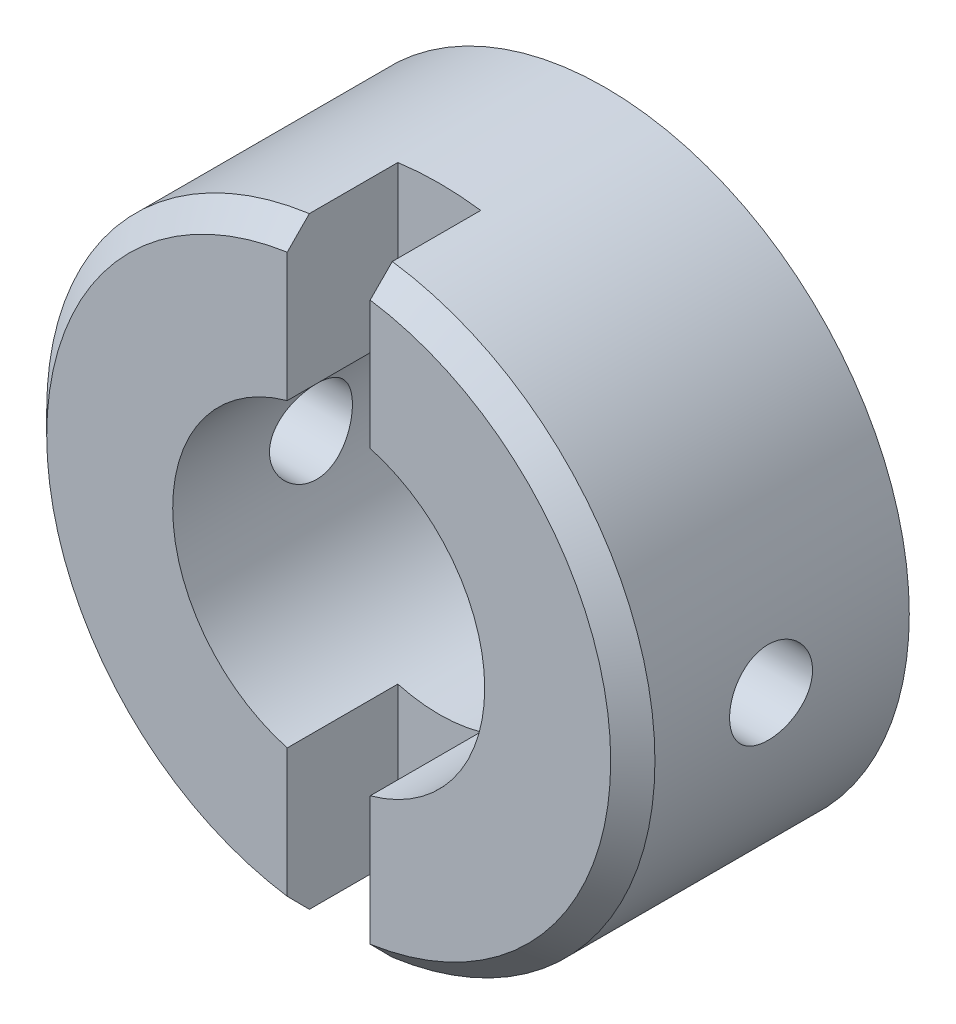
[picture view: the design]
ISO-10303-21;
HEADER;
FILE_DESCRIPTION(('STEP AP214'),'2;1');
FILE_NAME('part.step','',(''),(''),'','','');
FILE_SCHEMA(('AUTOMOTIVE_DESIGN { 1 0 10303 214 1 1 1 1 }'));
ENDSEC;
DATA;
#1=APPLICATION_CONTEXT('core data for automotive mechanical design processes');
#2=APPLICATION_PROTOCOL_DEFINITION('international standard','automotive_design',2000,#1);
#3=PRODUCT_CONTEXT('',#1,'mechanical');
#4=PRODUCT('Part','Part','',(#3));
#5=PRODUCT_RELATED_PRODUCT_CATEGORY('part','',(#4));
#6=PRODUCT_DEFINITION_FORMATION('','',#4);
#7=PRODUCT_DEFINITION_CONTEXT('part definition',#1,'design');
#8=PRODUCT_DEFINITION('design','',#6,#7);
#9=PRODUCT_DEFINITION_SHAPE('','',#8);
#10=(LENGTH_UNIT() NAMED_UNIT(*) SI_UNIT(.MILLI.,.METRE.));
#11=(NAMED_UNIT(*) PLANE_ANGLE_UNIT() SI_UNIT($,.RADIAN.));
#12=(NAMED_UNIT(*) SI_UNIT($,.STERADIAN.) SOLID_ANGLE_UNIT());
#13=UNCERTAINTY_MEASURE_WITH_UNIT(LENGTH_MEASURE(1.E-05),#10,'distance_accuracy_value','');
#14=(GEOMETRIC_REPRESENTATION_CONTEXT(3) GLOBAL_UNCERTAINTY_ASSIGNED_CONTEXT((#13)) GLOBAL_UNIT_ASSIGNED_CONTEXT((#10,
#11,#12)) REPRESENTATION_CONTEXT('',''));
#15=CARTESIAN_POINT('',(0.,0.,0.));
#16=DIRECTION('',(0.,0.,1.));
#17=DIRECTION('',(1.,0.,0.));
#18=AXIS2_PLACEMENT_3D('',#15,#16,#17);
#19=CARTESIAN_POINT('',(0.,0.,0.));
#20=DIRECTION('',(0.,0.,1.));
#21=DIRECTION('',(1.,0.,0.));
#22=AXIS2_PLACEMENT_3D('',#19,#20,#21);
#23=PLANE('',#22);
#24=DIRECTION('',(0.,1.,0.));
#25=VECTOR('',#24,1.);
#26=CARTESIAN_POINT('',(1.5,10.8972473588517,-1.70530256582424E-10));
#27=LINE('',#26,#25);
#28=CARTESIAN_POINT('',(1.5,-10.0891030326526,-1.70530256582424E-10));
#29=VERTEX_POINT('',#28);
#30=CARTESIAN_POINT('',(1.5,-5.43983887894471,-1.70530256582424E-10));
#31=VERTEX_POINT('',#30);
#32=EDGE_CURVE('E175',#29,#31,#27,.T.);
#33=ORIENTED_EDGE('',*,*,#32,.F.);
#34=CARTESIAN_POINT('',(0.,0.,0.));
#35=DIRECTION('',(0.,0.,1.));
#36=DIRECTION('',(1.,0.,0.));
#37=AXIS2_PLACEMENT_3D('',#34,#35,#36);
#38=CIRCLE('',#37,10.2);
#39=CARTESIAN_POINT('',(1.5,10.0891030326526,-1.70530256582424E-10));
#40=VERTEX_POINT('',#39);
#41=EDGE_CURVE('E191',#29,#40,#38,.T.);
#42=ORIENTED_EDGE('',*,*,#41,.T.);
#43=CARTESIAN_POINT('',(1.5,5.43983887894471,-1.70530256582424E-10));
#44=VERTEX_POINT('',#43);
#45=EDGE_CURVE('E171',#44,#40,#27,.T.);
#46=ORIENTED_EDGE('',*,*,#45,.F.);
#47=CARTESIAN_POINT('',(0.,0.,0.));
#48=DIRECTION('',(0.,0.,1.));
#49=DIRECTION('',(1.,0.,0.));
#50=AXIS2_PLACEMENT_3D('',#47,#48,#49);
#51=CIRCLE('',#50,5.642858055);
#52=EDGE_CURVE('E187',#31,#44,#51,.T.);
#53=ORIENTED_EDGE('',*,*,#52,.F.);
#54=EDGE_LOOP('',(#33,#42,#46,#53));
#55=FACE_BOUND('',#54,.T.);
#56=ADVANCED_FACE('F50',(#55),#23,.T.);
#57=CARTESIAN_POINT('',(0.,0.,0.));
#58=DIRECTION('',(0.,0.,-1.));
#59=DIRECTION('',(-1.,0.,0.));
#60=AXIS2_PLACEMENT_3D('',#57,#58,#59);
#61=CONICAL_SURFACE('',#60,10.2,0.785398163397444);
#62=CARTESIAN_POINT('',(1.5,-23.9829507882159,-13.8298133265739));
#63=CARTESIAN_POINT('',(1.5,-23.1697960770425,-13.0182561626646));
#64=CARTESIAN_POINT('',(1.5,-22.3565720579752,-12.2067684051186));
#65=CARTESIAN_POINT('',(1.5,-20.7298859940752,-10.5840045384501));
#66=CARTESIAN_POINT('',(1.5,-19.9164239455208,-9.77272843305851));
#67=CARTESIAN_POINT('',(1.5,-18.2888908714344,-8.15019003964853));
#68=CARTESIAN_POINT('',(1.5,-17.4748197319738,-7.33892786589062));
#69=CARTESIAN_POINT('',(1.5,-15.8462200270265,-5.71688912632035));
#70=CARTESIAN_POINT('',(1.5,-15.0316914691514,-4.90611255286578));
#71=CARTESIAN_POINT('',(1.5,-13.3679166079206,-3.25150833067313));
#72=CARTESIAN_POINT('',(1.5,-12.5186388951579,-2.40771224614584));
#73=CARTESIAN_POINT('',(1.5,-11.2436084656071,-1.14309787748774));
#74=CARTESIAN_POINT('',(1.5,-10.8184018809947,-0.721729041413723));
#75=CARTESIAN_POINT('',(1.5,-9.96746963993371,0.120480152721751));
#76=CARTESIAN_POINT('',(1.5,-9.54174398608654,0.54132051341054));
#77=CARTESIAN_POINT('',(1.5,-8.68962827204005,1.38212855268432));
#78=CARTESIAN_POINT('',(1.5,-8.26323839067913,1.8020964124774));
#79=CARTESIAN_POINT('',(1.5,-7.40927555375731,2.64084579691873));
#80=CARTESIAN_POINT('',(1.5,-6.98170257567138,3.05962729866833));
#81=CARTESIAN_POINT('',(1.5,-6.3388656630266,3.68624687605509));
#82=CARTESIAN_POINT('',(1.5,-6.12434986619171,3.89485219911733));
#83=CARTESIAN_POINT('',(1.5,-5.69463736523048,4.31136007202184));
#84=CARTESIAN_POINT('',(1.5,-5.47944066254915,4.51926262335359));
#85=CARTESIAN_POINT('',(1.5,-5.0481094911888,4.93407979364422));
#86=CARTESIAN_POINT('',(1.5,-4.83197505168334,5.1409944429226));
#87=CARTESIAN_POINT('',(1.5,-4.39834846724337,5.55339520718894));
#88=CARTESIAN_POINT('',(1.5,-4.1808563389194,5.75888133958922));
#89=CARTESIAN_POINT('',(1.5,-3.90376234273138,6.01802196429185));
#90=CARTESIAN_POINT('',(1.5,-3.84512620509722,6.07270919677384));
#91=CARTESIAN_POINT('',(1.5,-3.72768146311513,6.18189848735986));
#92=CARTESIAN_POINT('',(1.5,-3.66887285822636,6.23640054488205));
#93=CARTESIAN_POINT('',(1.5,-3.49215401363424,6.3995935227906));
#94=CARTESIAN_POINT('',(1.5,-3.37395242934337,6.50796966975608));
#95=CARTESIAN_POINT('',(1.5,-3.13700278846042,6.72317143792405));
#96=CARTESIAN_POINT('',(1.5,-3.01825878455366,6.83000151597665));
#97=CARTESIAN_POINT('',(1.5,-2.77941542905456,7.0421331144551));
#98=CARTESIAN_POINT('',(1.5,-2.65931612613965,7.14743468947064));
#99=CARTESIAN_POINT('',(1.5,-2.45761599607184,7.32107625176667));
#100=CARTESIAN_POINT('',(1.5,-2.37654045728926,7.39002559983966));
#101=CARTESIAN_POINT('',(1.5,-2.21332363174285,7.52664946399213));
#102=CARTESIAN_POINT('',(1.5,-2.13118237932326,7.59432402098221));
#103=CARTESIAN_POINT('',(1.5,-1.96490717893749,7.72847699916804));
#104=CARTESIAN_POINT('',(1.5,-1.88076292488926,7.79494269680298));
#105=CARTESIAN_POINT('',(1.5,-1.71065638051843,7.92549614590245));
#106=CARTESIAN_POINT('',(1.5,-1.62469433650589,7.98958421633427));
#107=CARTESIAN_POINT('',(1.5,-1.4489152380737,8.11541002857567));
#108=CARTESIAN_POINT('',(1.5,-1.35905816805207,8.17709235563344));
#109=CARTESIAN_POINT('',(1.5,-1.17582586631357,8.2953591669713));
#110=CARTESIAN_POINT('',(1.5,-1.08244624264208,8.35193696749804));
#111=CARTESIAN_POINT('',(1.5,-0.892287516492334,8.45646544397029));
#112=CARTESIAN_POINT('',(1.5,-0.795559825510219,8.50450780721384));
#113=CARTESIAN_POINT('',(1.5,-0.596885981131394,8.58809068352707));
#114=CARTESIAN_POINT('',(1.5,-0.494957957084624,8.62367162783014));
#115=CARTESIAN_POINT('',(1.5,-0.341566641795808,8.66233817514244));
#116=CARTESIAN_POINT('',(1.5,-0.291923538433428,8.67265748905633));
#117=CARTESIAN_POINT('',(1.5,-0.191872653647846,8.68858310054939));
#118=CARTESIAN_POINT('',(1.5,-0.141464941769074,8.694189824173));
#119=CARTESIAN_POINT('',(1.5,-0.0404708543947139,8.70029847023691));
#120=CARTESIAN_POINT('',(1.5,0.0101146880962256,8.7008139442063));
#121=CARTESIAN_POINT('',(1.5,0.111080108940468,8.69673902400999));
#122=CARTESIAN_POINT('',(1.5,0.161459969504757,8.69214819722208));
#123=CARTESIAN_POINT('',(1.5,0.261112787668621,8.6782367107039));
#124=CARTESIAN_POINT('',(1.5,0.310391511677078,8.66895654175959));
#125=CARTESIAN_POINT('',(1.5,0.407983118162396,8.64623193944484));
#126=CARTESIAN_POINT('',(1.5,0.456295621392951,8.63278590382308));
#127=CARTESIAN_POINT('',(1.5,0.552012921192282,8.60229924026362));
#128=CARTESIAN_POINT('',(1.5,0.599412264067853,8.58524170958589));
#129=CARTESIAN_POINT('',(1.5,0.693027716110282,8.54820030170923));
#130=CARTESIAN_POINT('',(1.5,0.739244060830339,8.52821701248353));
#131=CARTESIAN_POINT('',(1.5,0.877134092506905,8.46429884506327));
#132=CARTESIAN_POINT('',(1.5,0.967112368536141,8.41671652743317));
#133=CARTESIAN_POINT('',(1.5,1.14346729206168,8.31523950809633));
#134=CARTESIAN_POINT('',(1.5,1.22983935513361,8.26133708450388));
#135=CARTESIAN_POINT('',(1.5,1.40011689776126,8.1490927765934));
#136=CARTESIAN_POINT('',(1.5,1.48401123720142,8.09073413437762));
#137=CARTESIAN_POINT('',(1.5,1.6496160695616,7.97110725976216));
#138=CARTESIAN_POINT('',(1.5,1.73132761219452,7.90984046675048));
#139=CARTESIAN_POINT('',(1.5,1.89397218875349,7.78454603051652));
#140=CARTESIAN_POINT('',(1.5,1.97488799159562,7.72049612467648));
#141=CARTESIAN_POINT('',(1.5,2.13544471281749,7.59080709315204));
#142=CARTESIAN_POINT('',(1.5,2.21508549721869,7.52516780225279));
#143=CARTESIAN_POINT('',(1.5,2.37316238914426,7.3928600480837));
#144=CARTESIAN_POINT('',(1.5,2.45160103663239,7.32619461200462));
#145=CARTESIAN_POINT('',(1.5,2.60767842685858,7.19194269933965));
#146=CARTESIAN_POINT('',(1.5,2.68531720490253,7.12435626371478));
#147=CARTESIAN_POINT('',(1.5,2.91396863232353,6.92342200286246));
#148=CARTESIAN_POINT('',(1.5,3.06408132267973,6.78905078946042));
#149=CARTESIAN_POINT('',(1.5,3.36265984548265,6.51848828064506));
#150=CARTESIAN_POINT('',(1.5,3.51112561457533,6.38229691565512));
#151=CARTESIAN_POINT('',(1.5,3.8068978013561,6.10862812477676));
#152=CARTESIAN_POINT('',(1.5,3.95420408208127,5.9711505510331));
#153=CARTESIAN_POINT('',(1.5,4.24795127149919,5.69527329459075));
#154=CARTESIAN_POINT('',(1.5,4.39439217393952,5.55687360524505));
#155=CARTESIAN_POINT('',(1.5,4.83309667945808,5.14032506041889));
#156=CARTESIAN_POINT('',(1.5,5.12438996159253,4.86115489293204));
#157=CARTESIAN_POINT('',(1.5,5.70539561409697,4.30121832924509));
#158=CARTESIAN_POINT('',(1.5,5.99510809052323,4.02045204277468));
#159=CARTESIAN_POINT('',(1.5,6.57050259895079,3.46077976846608));
#160=CARTESIAN_POINT('',(1.5,6.85619526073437,3.18188470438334));
#161=CARTESIAN_POINT('',(1.5,7.42688642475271,2.62337574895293));
#162=CARTESIAN_POINT('',(1.5,7.71188491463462,2.34376184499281));
#163=CARTESIAN_POINT('',(1.5,8.56587556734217,1.50442258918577));
#164=CARTESIAN_POINT('',(1.5,9.13412608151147,0.943942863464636));
#165=CARTESIAN_POINT('',(1.5,10.2940945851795,-0.202420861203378));
#166=CARTESIAN_POINT('',(1.5,10.8857636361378,-0.788354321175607));
#167=CARTESIAN_POINT('',(1.5,12.0683546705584,-1.96097714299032));
#168=CARTESIAN_POINT('',(1.5,12.6592766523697,-2.54766650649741));
#169=CARTESIAN_POINT('',(1.5,14.4315473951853,-4.30867310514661));
#170=CARTESIAN_POINT('',(1.5,15.6121804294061,-5.48371043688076));
#171=CARTESIAN_POINT('',(1.5,17.9916039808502,-7.85372184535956));
#172=CARTESIAN_POINT('',(1.5,19.190379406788,-9.04871106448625));
#173=CARTESIAN_POINT('',(1.5,20.9880092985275,-10.8414978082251));
#174=CARTESIAN_POINT('',(1.5,21.5870724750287,-11.439086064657));
#175=CARTESIAN_POINT('',(1.5,22.7850878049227,-12.6343735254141));
#176=CARTESIAN_POINT('',(1.5,23.384039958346,-13.2320727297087));
#177=CARTESIAN_POINT('',(1.5,23.9829507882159,-13.8298133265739));
#178=B_SPLINE_CURVE_WITH_KNOTS('',3,(#62,#63,#64,#65,#66,#67,#68,#69,#70,#71,#72,#73,#74,#75,
#76,#77,#78,#79,#80,#81,#82,#83,#84,#85,#86,#87,#88,#89,#90,#91,#92,#93,#94,#95,#96,#97,#98,#99,
#100,#101,#102,#103,#104,#105,#106,#107,#108,#109,#110,#111,#112,#113,#114,#115,#116,#117,#118,
#119,#120,#121,#122,#123,#124,#125,#126,#127,#128,#129,#130,#131,#132,#133,#134,#135,#136,#137,
#138,#139,#140,#141,#142,#143,#144,#145,#146,#147,#148,#149,#150,#151,#152,#153,#154,#155,#156,
#157,#158,#159,#160,#161,#162,#163,#164,#165,#166,#167,#168,#169,#170,#171,#172,#173,#174,#175,
#176,#177),.UNSPECIFIED.,.F.,.F.,(4,2,2,2,2,2,2,2,2,2,2,2,2,2,2,2,2,2,2,2,2,2,2,2,2,2,2,2,2,2,2,
2,2,2,2,2,2,2,2,2,2,2,2,2,2,2,2,2,2,2,2,2,2,2,2,2,2,4),(0.,3.44653605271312,6.89312922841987,
10.3409868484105,13.7887887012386,17.3803581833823,19.1762340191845,20.9721008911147,
22.767547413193,24.5630283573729,25.4606903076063,26.358350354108,27.2559826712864,
28.1536040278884,28.3941447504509,28.6346862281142,29.1157761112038,29.5949495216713,
30.0741057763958,30.3933849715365,30.7126539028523,31.0343095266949,31.3559218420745,
31.6827820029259,32.0100641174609,32.3335843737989,32.6560450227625,32.8079667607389,
32.959874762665,33.1113783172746,33.2628947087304,33.4131246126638,33.5634123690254,
33.7144197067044,33.8653967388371,34.1703035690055,34.4755868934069,34.7820808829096,
35.0884247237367,35.3979910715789,35.7075897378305,36.0164043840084,36.3252053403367,
36.9295836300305,37.5339850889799,38.1384569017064,38.7429330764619,39.9533293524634,
41.1636433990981,42.3613996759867,43.559177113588,45.9536288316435,48.451729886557,
50.949836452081,55.9469807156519,61.0249285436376,63.5634114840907,66.1018937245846),.UNSPECIFIED.);
#179=CARTESIAN_POINT('',(1.5,-10.8972473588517,-0.800000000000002));
#180=VERTEX_POINT('',#179);
#181=EDGE_CURVE('E283',#180,#29,#178,.T.);
#182=ORIENTED_EDGE('',*,*,#181,.F.);
#183=CARTESIAN_POINT('',(0.,0.,-0.799999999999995));
#184=DIRECTION('',(0.,0.,1.));
#185=DIRECTION('',(1.,0.,0.));
#186=AXIS2_PLACEMENT_3D('',#183,#184,#185);
#187=CIRCLE('',#186,11.);
#188=CARTESIAN_POINT('',(1.5,10.8972473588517,-0.8));
#189=VERTEX_POINT('',#188);
#190=EDGE_CURVE('E196',#189,#180,#187,.F.);
#191=ORIENTED_EDGE('',*,*,#190,.F.);
#192=EDGE_CURVE('E210',#40,#189,#178,.T.);
#193=ORIENTED_EDGE('',*,*,#192,.F.);
#194=ORIENTED_EDGE('',*,*,#41,.F.);
#195=EDGE_LOOP('',(#182,#191,#193,#194));
#196=FACE_BOUND('',#195,.T.);
#197=ADVANCED_FACE('F259',(#196),#61,.T.);
#198=CARTESIAN_POINT('',(0.,0.,-10.));
#199=DIRECTION('',(0.,0.,1.));
#200=DIRECTION('',(1.,0.,0.));
#201=AXIS2_PLACEMENT_3D('',#198,#199,#200);
#202=CYLINDRICAL_SURFACE('',#201,11.);
#203=CARTESIAN_POINT('',(-11.,0.,-6.5));
#204=CARTESIAN_POINT('',(-10.9999987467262,-0.0838384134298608,-6.49999648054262));
#205=CARTESIAN_POINT('',(-10.9990314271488,-0.167727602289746,-6.49294740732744));
#206=CARTESIAN_POINT('',(-10.9952656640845,-0.333167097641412,-6.46494111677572));
#207=CARTESIAN_POINT('',(-10.992465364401,-0.414714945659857,-6.44396980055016));
#208=CARTESIAN_POINT('',(-10.9853487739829,-0.573053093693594,-6.38875226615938));
#209=CARTESIAN_POINT('',(-10.9810335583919,-0.649846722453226,-6.35451546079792));
#210=CARTESIAN_POINT('',(-10.971365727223,-0.79658530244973,-6.27376047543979));
#211=CARTESIAN_POINT('',(-10.9660132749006,-0.866531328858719,-6.22724422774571));
#212=CARTESIAN_POINT('',(-10.9548285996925,-0.998057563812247,-6.12292778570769));
#213=CARTESIAN_POINT('',(-10.9489937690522,-1.05958678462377,-6.06506357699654));
#214=CARTESIAN_POINT('',(-10.9375227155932,-1.17209333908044,-5.93983138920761));
#215=CARTESIAN_POINT('',(-10.9318865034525,-1.22307010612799,-5.87246290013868));
#216=CARTESIAN_POINT('',(-10.9214253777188,-1.31321850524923,-5.72979806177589));
#217=CARTESIAN_POINT('',(-10.916603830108,-1.35234166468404,-5.65447081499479));
#218=CARTESIAN_POINT('',(-10.9083529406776,-1.41736264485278,-5.49823818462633));
#219=CARTESIAN_POINT('',(-10.904923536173,-1.44326106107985,-5.4173330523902));
#220=CARTESIAN_POINT('',(-10.8998704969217,-1.4809409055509,-5.25277375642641));
#221=CARTESIAN_POINT('',(-10.8982357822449,-1.49280898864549,-5.16913978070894));
#222=CARTESIAN_POINT('',(-10.8969234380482,-1.50235955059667,-5.00105252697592));
#223=CARTESIAN_POINT('',(-10.8972457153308,-1.50004270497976,-4.91659928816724));
#224=CARTESIAN_POINT('',(-10.8998008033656,-1.4813601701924,-4.7498782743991));
#225=CARTESIAN_POINT('',(-10.9020205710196,-1.4650903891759,-4.66759952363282));
#226=CARTESIAN_POINT('',(-10.9081001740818,-1.419113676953,-4.50695095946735));
#227=CARTESIAN_POINT('',(-10.911960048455,-1.38940642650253,-4.42858123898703));
#228=CARTESIAN_POINT('',(-10.920899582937,-1.31729641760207,-4.27768007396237));
#229=CARTESIAN_POINT('',(-10.9259831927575,-1.27485243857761,-4.20516857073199));
#230=CARTESIAN_POINT('',(-10.9367944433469,-1.1785032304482,-4.06826085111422));
#231=CARTESIAN_POINT('',(-10.9425221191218,-1.12459737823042,-4.00386507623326));
#232=CARTESIAN_POINT('',(-10.954033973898,-1.006325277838,-3.88446044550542));
#233=CARTESIAN_POINT('',(-10.9598182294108,-0.941876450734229,-3.82953335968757));
#234=CARTESIAN_POINT('',(-10.9707474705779,-0.804630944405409,-3.73126350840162));
#235=CARTESIAN_POINT('',(-10.9758924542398,-0.73183423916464,-3.68792077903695));
#236=CARTESIAN_POINT('',(-10.9849675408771,-0.579892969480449,-3.61404813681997));
#237=CARTESIAN_POINT('',(-10.9888971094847,-0.500745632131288,-3.58352385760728));
#238=CARTESIAN_POINT('',(-10.9950939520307,-0.338383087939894,-3.5362221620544));
#239=CARTESIAN_POINT('',(-10.997361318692,-0.25516810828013,-3.51944397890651));
#240=CARTESIAN_POINT('',(-10.9999661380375,-0.0877389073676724,-3.50021791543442));
#241=CARTESIAN_POINT('',(-11.0003187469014,-0.00353783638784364,-3.49765749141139));
#242=CARTESIAN_POINT('',(-10.9990953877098,0.164092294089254,-3.50664187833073));
#243=CARTESIAN_POINT('',(-10.9975194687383,0.247521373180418,-3.51818633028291));
#244=CARTESIAN_POINT('',(-10.9926255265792,0.410903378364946,-3.55495922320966));
#245=CARTESIAN_POINT('',(-10.9893144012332,0.490868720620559,-3.58013349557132));
#246=CARTESIAN_POINT('',(-10.9813204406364,0.645443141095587,-3.64339475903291));
#247=CARTESIAN_POINT('',(-10.9766375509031,0.720052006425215,-3.68148226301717));
#248=CARTESIAN_POINT('',(-10.9663836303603,0.86229489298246,-3.76975753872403));
#249=CARTESIAN_POINT('',(-10.960807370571,0.929883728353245,-3.82001750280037));
#250=CARTESIAN_POINT('',(-10.9494055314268,1.05570701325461,-3.93110957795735));
#251=CARTESIAN_POINT('',(-10.9435799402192,1.11394101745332,-3.99194219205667));
#252=CARTESIAN_POINT('',(-10.9322886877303,1.21980532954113,-4.12295083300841));
#253=CARTESIAN_POINT('',(-10.9268257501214,1.26736066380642,-4.19318771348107));
#254=CARTESIAN_POINT('',(-10.9169246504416,1.34999839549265,-4.34071830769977));
#255=CARTESIAN_POINT('',(-10.9124864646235,1.38508108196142,-4.41801185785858));
#256=CARTESIAN_POINT('',(-10.9051564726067,1.44165849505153,-4.57722775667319));
#257=CARTESIAN_POINT('',(-10.902259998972,1.46319427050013,-4.65913529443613));
#258=CARTESIAN_POINT('',(-10.8983284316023,1.49219810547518,-4.82544652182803));
#259=CARTESIAN_POINT('',(-10.8972932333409,1.499666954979,-4.90985007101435));
#260=CARTESIAN_POINT('',(-10.8972048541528,1.50030856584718,-5.07801097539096));
#261=CARTESIAN_POINT('',(-10.8981353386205,1.49359914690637,-5.1617678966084));
#262=CARTESIAN_POINT('',(-10.9018382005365,1.46632546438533,-5.32695113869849));
#263=CARTESIAN_POINT('',(-10.9046105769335,1.44576120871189,-5.40837746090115));
#264=CARTESIAN_POINT('',(-10.9116795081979,1.3914005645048,-5.56656513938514));
#265=CARTESIAN_POINT('',(-10.9159752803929,1.35761096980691,-5.64332886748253));
#266=CARTESIAN_POINT('',(-10.925608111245,1.2777703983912,-5.79011629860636));
#267=CARTESIAN_POINT('',(-10.9309451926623,1.23171915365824,-5.86013985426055));
#268=CARTESIAN_POINT('',(-10.9421122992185,1.12822915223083,-5.99206003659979));
#269=CARTESIAN_POINT('',(-10.9479459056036,1.07070278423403,-6.05388763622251));
#270=CARTESIAN_POINT('',(-10.9594178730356,0.946079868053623,-6.16705534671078));
#271=CARTESIAN_POINT('',(-10.9650561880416,0.87898108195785,-6.21839299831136));
#272=CARTESIAN_POINT('',(-10.9755309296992,0.736765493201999,-6.30932596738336));
#273=CARTESIAN_POINT('',(-10.9803636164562,0.661613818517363,-6.34886715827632));
#274=CARTESIAN_POINT('',(-10.9886453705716,0.505709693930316,-6.41470948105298));
#275=CARTESIAN_POINT('',(-10.9920959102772,0.424963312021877,-6.4410247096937));
#276=CARTESIAN_POINT('',(-10.9964117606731,0.28651859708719,-6.47351043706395));
#277=CARTESIAN_POINT('',(-10.9977506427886,0.229685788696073,-6.48342936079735));
#278=CARTESIAN_POINT('',(-10.9995451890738,0.115243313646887,-6.49667532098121));
#279=CARTESIAN_POINT('',(-11.0000008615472,0.0576336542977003,-6.50000241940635));
#280=CARTESIAN_POINT('',(-11.,0.,-6.5));
#281=B_SPLINE_CURVE_WITH_KNOTS('',3,(#203,#204,#205,#206,#207,#208,#209,#210,#211,#212,#213,
#214,#215,#216,#217,#218,#219,#220,#221,#222,#223,#224,#225,#226,#227,#228,#229,#230,#231,#232,
#233,#234,#235,#236,#237,#238,#239,#240,#241,#242,#243,#244,#245,#246,#247,#248,#249,#250,#251,
#252,#253,#254,#255,#256,#257,#258,#259,#260,#261,#262,#263,#264,#265,#266,#267,#268,#269,#270,
#271,#272,#273,#274,#275,#276,#277,#278,#279,#280),.UNSPECIFIED.,.T.,.F.,(4,2,2,2,2,2,2,2,2,2,2,
2,2,2,2,2,2,2,2,2,2,2,2,2,2,2,2,2,2,2,2,2,2,2,2,2,2,2,4),(0.,0.251304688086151,
0.502864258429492,0.754245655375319,1.00558751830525,1.25839025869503,1.51120656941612,
1.76504317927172,2.01886835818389,2.27111752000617,2.52335466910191,2.77387178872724,
3.02439486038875,3.27573762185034,3.52709405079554,3.78052284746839,4.03395243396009,
4.28749328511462,4.54101999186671,4.79253696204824,5.04404753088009,5.29456578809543,
5.54509399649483,5.79714607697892,6.04921015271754,6.30299215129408,6.55676826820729,
6.80977166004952,7.0627608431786,7.3136559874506,7.56455098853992,7.81531727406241,
8.0660890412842,8.31885423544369,8.5716786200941,8.82564582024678,9.07934175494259,
9.25209960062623,9.42485582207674),.UNSPECIFIED.);
#282=CARTESIAN_POINT('',(-11.,0.,-6.5));
#283=VERTEX_POINT('',#282);
#284=EDGE_CURVE('E160',#283,#283,#281,.T.);
#285=ORIENTED_EDGE('',*,*,#284,.F.);
#286=EDGE_LOOP('',(#285));
#287=FACE_BOUND('',#286,.T.);
#288=CARTESIAN_POINT('',(11.,0.,-6.5));
#289=CARTESIAN_POINT('',(10.9999987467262,0.0838384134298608,-6.49999648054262));
#290=CARTESIAN_POINT('',(10.9990314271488,0.167727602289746,-6.49294740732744));
#291=CARTESIAN_POINT('',(10.9952656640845,0.333167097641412,-6.46494111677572));
#292=CARTESIAN_POINT('',(10.992465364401,0.414714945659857,-6.44396980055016));
#293=CARTESIAN_POINT('',(10.9853487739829,0.573053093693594,-6.38875226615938));
#294=CARTESIAN_POINT('',(10.9810335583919,0.649846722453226,-6.35451546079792));
#295=CARTESIAN_POINT('',(10.971365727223,0.79658530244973,-6.27376047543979));
#296=CARTESIAN_POINT('',(10.9660132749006,0.866531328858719,-6.22724422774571));
#297=CARTESIAN_POINT('',(10.9548285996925,0.998057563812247,-6.12292778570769));
#298=CARTESIAN_POINT('',(10.9489937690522,1.05958678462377,-6.06506357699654));
#299=CARTESIAN_POINT('',(10.9375227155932,1.17209333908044,-5.93983138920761));
#300=CARTESIAN_POINT('',(10.9318865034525,1.22307010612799,-5.87246290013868));
#301=CARTESIAN_POINT('',(10.9214253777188,1.31321850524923,-5.72979806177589));
#302=CARTESIAN_POINT('',(10.916603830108,1.35234166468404,-5.65447081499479));
#303=CARTESIAN_POINT('',(10.9083529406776,1.41736264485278,-5.49823818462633));
#304=CARTESIAN_POINT('',(10.904923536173,1.44326106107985,-5.4173330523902));
#305=CARTESIAN_POINT('',(10.8998704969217,1.4809409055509,-5.25277375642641));
#306=CARTESIAN_POINT('',(10.8982357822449,1.49280898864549,-5.16913978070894));
#307=CARTESIAN_POINT('',(10.8969234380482,1.50235955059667,-5.00105252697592));
#308=CARTESIAN_POINT('',(10.8972457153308,1.50004270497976,-4.91659928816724));
#309=CARTESIAN_POINT('',(10.8998008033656,1.4813601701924,-4.7498782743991));
#310=CARTESIAN_POINT('',(10.9020205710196,1.4650903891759,-4.66759952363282));
#311=CARTESIAN_POINT('',(10.9081001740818,1.419113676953,-4.50695095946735));
#312=CARTESIAN_POINT('',(10.911960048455,1.38940642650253,-4.42858123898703));
#313=CARTESIAN_POINT('',(10.920899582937,1.31729641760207,-4.27768007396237));
#314=CARTESIAN_POINT('',(10.9259831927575,1.27485243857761,-4.20516857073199));
#315=CARTESIAN_POINT('',(10.9367944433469,1.1785032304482,-4.06826085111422));
#316=CARTESIAN_POINT('',(10.9425221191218,1.12459737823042,-4.00386507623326));
#317=CARTESIAN_POINT('',(10.954033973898,1.006325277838,-3.88446044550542));
#318=CARTESIAN_POINT('',(10.9598182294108,0.941876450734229,-3.82953335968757));
#319=CARTESIAN_POINT('',(10.9707474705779,0.804630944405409,-3.73126350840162));
#320=CARTESIAN_POINT('',(10.9758924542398,0.73183423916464,-3.68792077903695));
#321=CARTESIAN_POINT('',(10.9849675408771,0.579892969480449,-3.61404813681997));
#322=CARTESIAN_POINT('',(10.9888971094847,0.500745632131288,-3.58352385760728));
#323=CARTESIAN_POINT('',(10.9950939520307,0.338383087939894,-3.5362221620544));
#324=CARTESIAN_POINT('',(10.997361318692,0.25516810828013,-3.51944397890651));
#325=CARTESIAN_POINT('',(10.9999661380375,0.0877389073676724,-3.50021791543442));
#326=CARTESIAN_POINT('',(11.0003187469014,0.00353783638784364,-3.49765749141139));
#327=CARTESIAN_POINT('',(10.9990953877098,-0.164092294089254,-3.50664187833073));
#328=CARTESIAN_POINT('',(10.9975194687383,-0.247521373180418,-3.51818633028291));
#329=CARTESIAN_POINT('',(10.9926255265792,-0.410903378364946,-3.55495922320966));
#330=CARTESIAN_POINT('',(10.9893144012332,-0.490868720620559,-3.58013349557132));
#331=CARTESIAN_POINT('',(10.9813204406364,-0.645443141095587,-3.64339475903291));
#332=CARTESIAN_POINT('',(10.9766375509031,-0.720052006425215,-3.68148226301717));
#333=CARTESIAN_POINT('',(10.9663836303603,-0.86229489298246,-3.76975753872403));
#334=CARTESIAN_POINT('',(10.960807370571,-0.929883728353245,-3.82001750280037));
#335=CARTESIAN_POINT('',(10.9494055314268,-1.05570701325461,-3.93110957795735));
#336=CARTESIAN_POINT('',(10.9435799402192,-1.11394101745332,-3.99194219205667));
#337=CARTESIAN_POINT('',(10.9322886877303,-1.21980532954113,-4.12295083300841));
#338=CARTESIAN_POINT('',(10.9268257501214,-1.26736066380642,-4.19318771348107));
#339=CARTESIAN_POINT('',(10.9169246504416,-1.34999839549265,-4.34071830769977));
#340=CARTESIAN_POINT('',(10.9124864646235,-1.38508108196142,-4.41801185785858));
#341=CARTESIAN_POINT('',(10.9051564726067,-1.44165849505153,-4.57722775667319));
#342=CARTESIAN_POINT('',(10.902259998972,-1.46319427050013,-4.65913529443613));
#343=CARTESIAN_POINT('',(10.8983284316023,-1.49219810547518,-4.82544652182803));
#344=CARTESIAN_POINT('',(10.8972932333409,-1.499666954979,-4.90985007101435));
#345=CARTESIAN_POINT('',(10.8972048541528,-1.50030856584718,-5.07801097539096));
#346=CARTESIAN_POINT('',(10.8981353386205,-1.49359914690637,-5.1617678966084));
#347=CARTESIAN_POINT('',(10.9018382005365,-1.46632546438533,-5.32695113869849));
#348=CARTESIAN_POINT('',(10.9046105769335,-1.44576120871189,-5.40837746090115));
#349=CARTESIAN_POINT('',(10.9116795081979,-1.3914005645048,-5.56656513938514));
#350=CARTESIAN_POINT('',(10.9159752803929,-1.35761096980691,-5.64332886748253));
#351=CARTESIAN_POINT('',(10.925608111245,-1.2777703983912,-5.79011629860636));
#352=CARTESIAN_POINT('',(10.9309451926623,-1.23171915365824,-5.86013985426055));
#353=CARTESIAN_POINT('',(10.9421122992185,-1.12822915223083,-5.99206003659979));
#354=CARTESIAN_POINT('',(10.9479459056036,-1.07070278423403,-6.05388763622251));
#355=CARTESIAN_POINT('',(10.9594178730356,-0.946079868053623,-6.16705534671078));
#356=CARTESIAN_POINT('',(10.9650561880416,-0.87898108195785,-6.21839299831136));
#357=CARTESIAN_POINT('',(10.9755309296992,-0.736765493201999,-6.30932596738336));
#358=CARTESIAN_POINT('',(10.9803636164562,-0.661613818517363,-6.34886715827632));
#359=CARTESIAN_POINT('',(10.9886453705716,-0.505709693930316,-6.41470948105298));
#360=CARTESIAN_POINT('',(10.9920959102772,-0.424963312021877,-6.4410247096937));
#361=CARTESIAN_POINT('',(10.9964117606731,-0.28651859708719,-6.47351043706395));
#362=CARTESIAN_POINT('',(10.9977506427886,-0.229685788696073,-6.48342936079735));
#363=CARTESIAN_POINT('',(10.9995451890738,-0.115243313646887,-6.49667532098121));
#364=CARTESIAN_POINT('',(11.0000008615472,-0.0576336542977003,-6.50000241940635));
#365=CARTESIAN_POINT('',(11.,0.,-6.5));
#366=B_SPLINE_CURVE_WITH_KNOTS('',3,(#288,#289,#290,#291,#292,#293,#294,#295,#296,#297,#298,
#299,#300,#301,#302,#303,#304,#305,#306,#307,#308,#309,#310,#311,#312,#313,#314,#315,#316,#317,
#318,#319,#320,#321,#322,#323,#324,#325,#326,#327,#328,#329,#330,#331,#332,#333,#334,#335,#336,
#337,#338,#339,#340,#341,#342,#343,#344,#345,#346,#347,#348,#349,#350,#351,#352,#353,#354,#355,
#356,#357,#358,#359,#360,#361,#362,#363,#364,#365),.UNSPECIFIED.,.T.,.F.,(4,2,2,2,2,2,2,2,2,2,2,
2,2,2,2,2,2,2,2,2,2,2,2,2,2,2,2,2,2,2,2,2,2,2,2,2,2,2,4),(0.,0.251304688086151,
0.502864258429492,0.754245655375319,1.00558751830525,1.25839025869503,1.51120656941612,
1.76504317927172,2.01886835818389,2.27111752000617,2.52335466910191,2.77387178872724,
3.02439486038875,3.27573762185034,3.52709405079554,3.78052284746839,4.03395243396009,
4.28749328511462,4.54101999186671,4.79253696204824,5.04404753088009,5.29456578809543,
5.54509399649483,5.79714607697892,6.04921015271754,6.30299215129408,6.55676826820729,
6.80977166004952,7.0627608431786,7.3136559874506,7.56455098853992,7.81531727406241,
8.0660890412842,8.31885423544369,8.5716786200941,8.82564582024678,9.07934175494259,
9.25209960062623,9.42485582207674),.UNSPECIFIED.);
#367=CARTESIAN_POINT('',(11.,0.,-6.5));
#368=VERTEX_POINT('',#367);
#369=EDGE_CURVE('E242',#368,#368,#366,.T.);
#370=ORIENTED_EDGE('',*,*,#369,.F.);
#371=EDGE_LOOP('',(#370));
#372=FACE_BOUND('',#371,.T.);
#373=DIRECTION('',(0.,0.,1.));
#374=VECTOR('',#373,1.);
#375=CARTESIAN_POINT('',(1.5,-10.8972473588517,-32.2036033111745));
#376=LINE('',#375,#374);
#377=CARTESIAN_POINT('',(1.5,-10.8972473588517,-4.));
#378=VERTEX_POINT('',#377);
#379=EDGE_CURVE('E135',#378,#180,#376,.T.);
#380=ORIENTED_EDGE('',*,*,#379,.F.);
#381=CARTESIAN_POINT('',(0.,0.,-4.));
#382=DIRECTION('',(0.,0.,1.));
#383=DIRECTION('',(1.,0.,0.));
#384=AXIS2_PLACEMENT_3D('',#381,#382,#383);
#385=CIRCLE('',#384,11.);
#386=CARTESIAN_POINT('',(-1.5,-10.8972473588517,-4.));
#387=VERTEX_POINT('',#386);
#388=EDGE_CURVE('E139',#378,#387,#385,.F.);
#389=ORIENTED_EDGE('',*,*,#388,.T.);
#390=DIRECTION('',(0.,0.,1.));
#391=VECTOR('',#390,1.);
#392=CARTESIAN_POINT('',(-1.5,-10.8972473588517,-32.2036033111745));
#393=LINE('',#392,#391);
#394=CARTESIAN_POINT('',(-1.5,-10.8972473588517,-0.799999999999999));
#395=VERTEX_POINT('',#394);
#396=EDGE_CURVE('E124',#387,#395,#393,.T.);
#397=ORIENTED_EDGE('',*,*,#396,.T.);
#398=CARTESIAN_POINT('',(-1.5,10.8972473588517,-0.799999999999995));
#399=VERTEX_POINT('',#398);
#400=EDGE_CURVE('E198',#395,#399,#187,.F.);
#401=ORIENTED_EDGE('',*,*,#400,.T.);
#402=DIRECTION('',(0.,0.,1.));
#403=VECTOR('',#402,1.);
#404=CARTESIAN_POINT('',(-1.5,10.8972473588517,-32.2036033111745));
#405=LINE('',#404,#403);
#406=CARTESIAN_POINT('',(-1.5,10.8972473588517,-4.));
#407=VERTEX_POINT('',#406);
#408=EDGE_CURVE('E67',#407,#399,#405,.T.);
#409=ORIENTED_EDGE('',*,*,#408,.F.);
#410=CARTESIAN_POINT('',(0.,0.,-4.));
#411=DIRECTION('',(0.,0.,1.));
#412=DIRECTION('',(1.,0.,0.));
#413=AXIS2_PLACEMENT_3D('',#410,#411,#412);
#414=CIRCLE('',#413,11.);
#415=CARTESIAN_POINT('',(1.5,10.8972473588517,-4.));
#416=VERTEX_POINT('',#415);
#417=EDGE_CURVE('E168',#407,#416,#414,.F.);
#418=ORIENTED_EDGE('',*,*,#417,.T.);
#419=DIRECTION('',(0.,0.,1.));
#420=VECTOR('',#419,1.);
#421=CARTESIAN_POINT('',(1.5,10.8972473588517,-32.2036033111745));
#422=LINE('',#421,#420);
#423=EDGE_CURVE('E147',#416,#189,#422,.T.);
#424=ORIENTED_EDGE('',*,*,#423,.T.);
#425=ORIENTED_EDGE('',*,*,#190,.T.);
#426=EDGE_LOOP('',(#380,#389,#397,#401,#409,#418,#424,#425));
#427=FACE_BOUND('',#426,.T.);
#428=CARTESIAN_POINT('',(0.,0.,-10.));
#429=DIRECTION('',(0.,0.,1.));
#430=DIRECTION('',(1.,0.,0.));
#431=AXIS2_PLACEMENT_3D('',#428,#429,#430);
#432=CIRCLE('',#431,11.);
#433=CARTESIAN_POINT('',(11.,0.,-10.));
#434=VERTEX_POINT('',#433);
#435=EDGE_CURVE('E188',#434,#434,#432,.T.);
#436=ORIENTED_EDGE('',*,*,#435,.T.);
#437=EDGE_LOOP('',(#436));
#438=FACE_BOUND('',#437,.T.);
#439=ADVANCED_FACE('F148',(#287,#372,#427,#438),#202,.T.);
#440=CARTESIAN_POINT('',(0.,0.,-10.));
#441=DIRECTION('',(0.,0.,1.));
#442=DIRECTION('',(1.,0.,0.));
#443=AXIS2_PLACEMENT_3D('',#440,#441,#442);
#444=PLANE('',#443);
#445=CARTESIAN_POINT('',(0.,0.,-10.));
#446=DIRECTION('',(0.,0.,1.));
#447=DIRECTION('',(1.,0.,0.));
#448=AXIS2_PLACEMENT_3D('',#445,#446,#447);
#449=CIRCLE('',#448,6.042858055);
#450=CARTESIAN_POINT('',(6.042858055,0.,-10.));
#451=VERTEX_POINT('',#450);
#452=EDGE_CURVE('E54',#451,#451,#449,.T.);
#453=ORIENTED_EDGE('',*,*,#452,.T.);
#454=EDGE_LOOP('',(#453));
#455=FACE_BOUND('',#454,.T.);
#456=ORIENTED_EDGE('',*,*,#435,.F.);
#457=EDGE_LOOP('',(#456));
#458=FACE_BOUND('',#457,.T.);
#459=ADVANCED_FACE('F229',(#455,#458),#444,.F.);
#460=DIRECTION('',(0.,-1.,0.));
#461=VECTOR('',#460,1.);
#462=CARTESIAN_POINT('',(-1.5,10.8972473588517,-1.70530256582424E-10));
#463=LINE('',#462,#461);
#464=CARTESIAN_POINT('',(-1.5,10.0891030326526,-1.70530256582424E-10));
#465=VERTEX_POINT('',#464);
#466=CARTESIAN_POINT('',(-1.5,5.43983887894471,-1.70530256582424E-10));
#467=VERTEX_POINT('',#466);
#468=EDGE_CURVE('E167',#465,#467,#463,.T.);
#469=ORIENTED_EDGE('',*,*,#468,.F.);
#470=CARTESIAN_POINT('',(-1.49999999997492,-10.0891030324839,0.));
#471=VERTEX_POINT('',#470);
#472=EDGE_CURVE('E199',#465,#471,#38,.T.);
#473=ORIENTED_EDGE('',*,*,#472,.T.);
#474=CARTESIAN_POINT('',(-1.5,-5.43983887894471,-1.70530256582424E-10));
#475=VERTEX_POINT('',#474);
#476=EDGE_CURVE('E65',#475,#471,#463,.T.);
#477=ORIENTED_EDGE('',*,*,#476,.F.);
#478=EDGE_CURVE('E186',#467,#475,#51,.T.);
#479=ORIENTED_EDGE('',*,*,#478,.F.);
#480=EDGE_LOOP('',(#469,#473,#477,#479));
#481=FACE_BOUND('',#480,.T.);
#482=ADVANCED_FACE('F226',(#481),#23,.T.);
#483=CARTESIAN_POINT('',(0.,0.,-10.));
#484=DIRECTION('',(0.,0.,1.));
#485=DIRECTION('',(1.,0.,0.));
#486=AXIS2_PLACEMENT_3D('',#483,#484,#485);
#487=CYLINDRICAL_SURFACE('',#486,5.642858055);
#488=CARTESIAN_POINT('',(0.,0.,-9.6));
#489=DIRECTION('',(0.,0.,1.));
#490=DIRECTION('',(1.,0.,0.));
#491=AXIS2_PLACEMENT_3D('',#488,#489,#490);
#492=CIRCLE('',#491,5.642858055);
#493=CARTESIAN_POINT('',(5.642858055,0.,-9.6));
#494=VERTEX_POINT('',#493);
#495=EDGE_CURVE('E12',#494,#494,#492,.F.);
#496=ORIENTED_EDGE('',*,*,#495,.T.);
#497=EDGE_LOOP('',(#496));
#498=FACE_BOUND('',#497,.T.);
#499=CARTESIAN_POINT('',(5.642858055,0.,-6.5));
#500=CARTESIAN_POINT('',(5.64285679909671,0.0827005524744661,-6.49999801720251));
#501=CARTESIAN_POINT('',(5.64102208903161,0.165422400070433,-6.49313768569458));
#502=CARTESIAN_POINT('',(5.63388122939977,0.328483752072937,-6.46592580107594));
#503=CARTESIAN_POINT('',(5.6285733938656,0.408822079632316,-6.44556769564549));
#504=CARTESIAN_POINT('',(5.6150722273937,0.564739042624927,-6.39206842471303));
#505=CARTESIAN_POINT('',(5.60688260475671,0.640323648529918,-6.35894368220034));
#506=CARTESIAN_POINT('',(5.58848370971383,0.784864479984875,-6.2809121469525));
#507=CARTESIAN_POINT('',(5.57827430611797,0.853820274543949,-6.23600458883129));
#508=CARTESIAN_POINT('',(5.55667527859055,0.984735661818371,-6.13458920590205));
#509=CARTESIAN_POINT('',(5.5452655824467,1.04652067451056,-6.077860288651));
#510=CARTESIAN_POINT('',(5.52268103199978,1.15982151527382,-5.95488518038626));
#511=CARTESIAN_POINT('',(5.51150620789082,1.2113360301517,-5.8886377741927));
#512=CARTESIAN_POINT('',(5.49045148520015,1.30348323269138,-5.74711466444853));
#513=CARTESIAN_POINT('',(5.48059691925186,1.34391536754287,-5.67170426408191));
#514=CARTESIAN_POINT('',(5.46359347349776,1.41145843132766,-5.51485177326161));
#515=CARTESIAN_POINT('',(5.45644409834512,1.43857179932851,-5.4334107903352));
#516=CARTESIAN_POINT('',(5.44586769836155,1.47810192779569,-5.26874167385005));
#517=CARTESIAN_POINT('',(5.44236068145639,1.49083507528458,-5.18559475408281));
#518=CARTESIAN_POINT('',(5.439227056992,1.50222964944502,-5.01827666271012));
#519=CARTESIAN_POINT('',(5.43959972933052,1.50089368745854,-4.93410568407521));
#520=CARTESIAN_POINT('',(5.4441117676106,1.48443921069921,-4.76959595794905));
#521=CARTESIAN_POINT('',(5.44814658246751,1.46970323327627,-4.68921562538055));
#522=CARTESIAN_POINT('',(5.45936091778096,1.42747958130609,-4.53211131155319));
#523=CARTESIAN_POINT('',(5.4665406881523,1.39999089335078,-4.45538762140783));
#524=CARTESIAN_POINT('',(5.48332809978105,1.33272966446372,-4.30677587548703));
#525=CARTESIAN_POINT('',(5.49296207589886,1.29282276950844,-4.23495172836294));
#526=CARTESIAN_POINT('',(5.5135581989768,1.2019516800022,-4.09888488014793));
#527=CARTESIAN_POINT('',(5.52452060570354,1.15098532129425,-4.03464366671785));
#528=CARTESIAN_POINT('',(5.54697385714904,1.03748478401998,-3.91338033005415));
#529=CARTESIAN_POINT('',(5.55847031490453,0.974629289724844,-3.85665957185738));
#530=CARTESIAN_POINT('',(5.58037768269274,0.840158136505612,-3.75450251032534));
#531=CARTESIAN_POINT('',(5.59078855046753,0.768542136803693,-3.7090666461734));
#532=CARTESIAN_POINT('',(5.60941508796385,0.618118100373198,-3.63063759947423));
#533=CARTESIAN_POINT('',(5.61762114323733,0.53928051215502,-3.59769866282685));
#534=CARTESIAN_POINT('',(5.63084393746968,0.376918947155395,-3.54562870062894));
#535=CARTESIAN_POINT('',(5.6358613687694,0.293395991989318,-3.52649467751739));
#536=CARTESIAN_POINT('',(5.64203700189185,0.126606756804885,-3.50305019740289));
#537=CARTESIAN_POINT('',(5.64330185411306,0.0434019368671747,-3.49832997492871));
#538=CARTESIAN_POINT('',(5.64213629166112,-0.122610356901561,-3.50271586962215));
#539=CARTESIAN_POINT('',(5.6397062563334,-0.20541787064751,-3.51182056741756));
#540=CARTESIAN_POINT('',(5.63149281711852,-0.366824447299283,-3.54326166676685));
#541=CARTESIAN_POINT('',(5.62576730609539,-0.445471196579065,-3.56536977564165));
#542=CARTESIAN_POINT('',(5.61161216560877,-0.597932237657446,-3.62192524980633));
#543=CARTESIAN_POINT('',(5.60318224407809,-0.67174600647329,-3.65637394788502));
#544=CARTESIAN_POINT('',(5.58430318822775,-0.814039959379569,-3.73739456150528));
#545=CARTESIAN_POINT('',(5.57381789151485,-0.882388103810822,-3.78418973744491));
#546=CARTESIAN_POINT('',(5.55204027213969,-1.0104056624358,-3.88829404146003));
#547=CARTESIAN_POINT('',(5.54074779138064,-1.07007336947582,-3.9456052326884));
#548=CARTESIAN_POINT('',(5.51823658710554,-1.18076101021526,-4.07102646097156));
#549=CARTESIAN_POINT('',(5.50702878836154,-1.23149192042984,-4.13939400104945));
#550=CARTESIAN_POINT('',(5.48630388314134,-1.32076686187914,-4.28390846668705));
#551=CARTESIAN_POINT('',(5.47678670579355,-1.35931140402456,-4.36005506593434));
#552=CARTESIAN_POINT('',(5.46062984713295,-1.4228293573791,-4.51758444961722));
#553=CARTESIAN_POINT('',(5.45397352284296,-1.44788148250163,-4.59893369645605));
#554=CARTESIAN_POINT('',(5.44428778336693,-1.48389078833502,-4.7648970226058));
#555=CARTESIAN_POINT('',(5.44125744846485,-1.49485154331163,-4.84951026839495));
#556=CARTESIAN_POINT('',(5.43924327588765,-1.50216234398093,-5.01664165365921));
#557=CARTESIAN_POINT('',(5.4401308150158,-1.49897678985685,-5.09913823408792));
#558=CARTESIAN_POINT('',(5.44555143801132,-1.47916189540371,-5.26237244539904));
#559=CARTESIAN_POINT('',(5.4500844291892,-1.46253289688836,-5.34311012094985));
#560=CARTESIAN_POINT('',(5.46220889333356,-1.41657159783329,-5.4999543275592));
#561=CARTESIAN_POINT('',(5.46977678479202,-1.38733711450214,-5.57609147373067));
#562=CARTESIAN_POINT('',(5.48711904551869,-1.31707074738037,-5.72243773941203));
#563=CARTESIAN_POINT('',(5.49689375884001,-1.27603702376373,-5.79264593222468));
#564=CARTESIAN_POINT('',(5.51790549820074,-1.18192697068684,-5.92735947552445));
#565=CARTESIAN_POINT('',(5.52917693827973,-1.12853345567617,-5.99163790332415));
#566=CARTESIAN_POINT('',(5.55171924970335,-1.0118234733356,-6.11047346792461));
#567=CARTESIAN_POINT('',(5.56299012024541,-0.948504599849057,-6.1650282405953));
#568=CARTESIAN_POINT('',(5.58454727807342,-0.81212026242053,-6.26400514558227));
#569=CARTESIAN_POINT('',(5.59480760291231,-0.738876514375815,-6.30818774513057));
#570=CARTESIAN_POINT('',(5.61290415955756,-0.585731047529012,-6.38354307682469));
#571=CARTESIAN_POINT('',(5.62074195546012,-0.505833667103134,-6.41472420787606));
#572=CARTESIAN_POINT('',(5.63208923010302,-0.355187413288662,-6.45909522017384));
#573=CARTESIAN_POINT('',(5.63609819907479,-0.285091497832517,-6.47439901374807));
#574=CARTESIAN_POINT('',(5.64148302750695,-0.143335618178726,-6.4948517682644));
#575=CARTESIAN_POINT('',(5.64285914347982,-0.0716758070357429,-6.50000171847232));
#576=CARTESIAN_POINT('',(5.642858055,0.,-6.5));
#577=B_SPLINE_CURVE_WITH_KNOTS('',3,(#499,#500,#501,#502,#503,#504,#505,#506,#507,#508,#509,
#510,#511,#512,#513,#514,#515,#516,#517,#518,#519,#520,#521,#522,#523,#524,#525,#526,#527,#528,
#529,#530,#531,#532,#533,#534,#535,#536,#537,#538,#539,#540,#541,#542,#543,#544,#545,#546,#547,
#548,#549,#550,#551,#552,#553,#554,#555,#556,#557,#558,#559,#560,#561,#562,#563,#564,#565,#566,
#567,#568,#569,#570,#571,#572,#573,#574,#575,#576),.UNSPECIFIED.,.T.,.F.,(4,2,2,2,2,2,2,2,2,2,2,
2,2,2,2,2,2,2,2,2,2,2,2,2,2,2,2,2,2,2,2,2,2,2,2,2,2,2,4),(0.,0.247838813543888,
0.495798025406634,0.743439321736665,0.991096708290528,1.2438859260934,1.49670744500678,
1.75384041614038,2.01092628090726,2.26223840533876,2.51350388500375,2.75781410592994,
3.00214374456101,3.24921454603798,3.49633373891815,3.75146021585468,4.00659662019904,
4.2628281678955,4.51900406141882,4.76782603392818,5.01662246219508,5.26117607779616,
5.505756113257,5.75510447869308,6.00450181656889,6.26088449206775,6.51725641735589,
6.77211602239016,7.0269109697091,7.27340437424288,7.51989151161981,7.76449941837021,
8.00914548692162,8.26094862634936,8.51281290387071,8.77002078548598,9.02706225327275,
9.24188280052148,9.45668241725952),.UNSPECIFIED.);
#578=CARTESIAN_POINT('',(5.642858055,0.,-6.5));
#579=VERTEX_POINT('',#578);
#580=EDGE_CURVE('E237',#579,#579,#577,.T.);
#581=ORIENTED_EDGE('',*,*,#580,.T.);
#582=EDGE_LOOP('',(#581));
#583=FACE_BOUND('',#582,.T.);
#584=CARTESIAN_POINT('',(-5.642858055,0.,-6.5));
#585=CARTESIAN_POINT('',(-5.64285679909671,-0.0827005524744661,-6.49999801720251));
#586=CARTESIAN_POINT('',(-5.64102208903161,-0.165422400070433,-6.49313768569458));
#587=CARTESIAN_POINT('',(-5.63388122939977,-0.328483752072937,-6.46592580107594));
#588=CARTESIAN_POINT('',(-5.6285733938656,-0.408822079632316,-6.44556769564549));
#589=CARTESIAN_POINT('',(-5.6150722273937,-0.564739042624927,-6.39206842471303));
#590=CARTESIAN_POINT('',(-5.60688260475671,-0.640323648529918,-6.35894368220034));
#591=CARTESIAN_POINT('',(-5.58848370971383,-0.784864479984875,-6.2809121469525));
#592=CARTESIAN_POINT('',(-5.57827430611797,-0.853820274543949,-6.23600458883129));
#593=CARTESIAN_POINT('',(-5.55667527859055,-0.984735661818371,-6.13458920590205));
#594=CARTESIAN_POINT('',(-5.5452655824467,-1.04652067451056,-6.077860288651));
#595=CARTESIAN_POINT('',(-5.52268103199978,-1.15982151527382,-5.95488518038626));
#596=CARTESIAN_POINT('',(-5.51150620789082,-1.2113360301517,-5.8886377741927));
#597=CARTESIAN_POINT('',(-5.49045148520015,-1.30348323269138,-5.74711466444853));
#598=CARTESIAN_POINT('',(-5.48059691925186,-1.34391536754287,-5.67170426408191));
#599=CARTESIAN_POINT('',(-5.46359347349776,-1.41145843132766,-5.51485177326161));
#600=CARTESIAN_POINT('',(-5.45644409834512,-1.43857179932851,-5.4334107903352));
#601=CARTESIAN_POINT('',(-5.44586769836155,-1.47810192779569,-5.26874167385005));
#602=CARTESIAN_POINT('',(-5.44236068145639,-1.49083507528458,-5.18559475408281));
#603=CARTESIAN_POINT('',(-5.439227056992,-1.50222964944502,-5.01827666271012));
#604=CARTESIAN_POINT('',(-5.43959972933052,-1.50089368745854,-4.93410568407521));
#605=CARTESIAN_POINT('',(-5.4441117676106,-1.48443921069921,-4.76959595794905));
#606=CARTESIAN_POINT('',(-5.44814658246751,-1.46970323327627,-4.68921562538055));
#607=CARTESIAN_POINT('',(-5.45936091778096,-1.42747958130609,-4.53211131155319));
#608=CARTESIAN_POINT('',(-5.4665406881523,-1.39999089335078,-4.45538762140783));
#609=CARTESIAN_POINT('',(-5.48332809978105,-1.33272966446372,-4.30677587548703));
#610=CARTESIAN_POINT('',(-5.49296207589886,-1.29282276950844,-4.23495172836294));
#611=CARTESIAN_POINT('',(-5.5135581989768,-1.2019516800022,-4.09888488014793));
#612=CARTESIAN_POINT('',(-5.52452060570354,-1.15098532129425,-4.03464366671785));
#613=CARTESIAN_POINT('',(-5.54697385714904,-1.03748478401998,-3.91338033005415));
#614=CARTESIAN_POINT('',(-5.55847031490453,-0.974629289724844,-3.85665957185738));
#615=CARTESIAN_POINT('',(-5.58037768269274,-0.840158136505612,-3.75450251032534));
#616=CARTESIAN_POINT('',(-5.59078855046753,-0.768542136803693,-3.7090666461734));
#617=CARTESIAN_POINT('',(-5.60941508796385,-0.618118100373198,-3.63063759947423));
#618=CARTESIAN_POINT('',(-5.61762114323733,-0.53928051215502,-3.59769866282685));
#619=CARTESIAN_POINT('',(-5.63084393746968,-0.376918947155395,-3.54562870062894));
#620=CARTESIAN_POINT('',(-5.6358613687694,-0.293395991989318,-3.52649467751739));
#621=CARTESIAN_POINT('',(-5.64203700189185,-0.126606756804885,-3.50305019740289));
#622=CARTESIAN_POINT('',(-5.64330185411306,-0.0434019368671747,-3.49832997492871));
#623=CARTESIAN_POINT('',(-5.64213629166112,0.122610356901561,-3.50271586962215));
#624=CARTESIAN_POINT('',(-5.6397062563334,0.20541787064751,-3.51182056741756));
#625=CARTESIAN_POINT('',(-5.63149281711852,0.366824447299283,-3.54326166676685));
#626=CARTESIAN_POINT('',(-5.62576730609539,0.445471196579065,-3.56536977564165));
#627=CARTESIAN_POINT('',(-5.61161216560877,0.597932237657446,-3.62192524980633));
#628=CARTESIAN_POINT('',(-5.60318224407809,0.67174600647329,-3.65637394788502));
#629=CARTESIAN_POINT('',(-5.58430318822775,0.814039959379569,-3.73739456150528));
#630=CARTESIAN_POINT('',(-5.57381789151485,0.882388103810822,-3.78418973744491));
#631=CARTESIAN_POINT('',(-5.55204027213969,1.0104056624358,-3.88829404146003));
#632=CARTESIAN_POINT('',(-5.54074779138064,1.07007336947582,-3.9456052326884));
#633=CARTESIAN_POINT('',(-5.51823658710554,1.18076101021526,-4.07102646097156));
#634=CARTESIAN_POINT('',(-5.50702878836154,1.23149192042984,-4.13939400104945));
#635=CARTESIAN_POINT('',(-5.48630388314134,1.32076686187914,-4.28390846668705));
#636=CARTESIAN_POINT('',(-5.47678670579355,1.35931140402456,-4.36005506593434));
#637=CARTESIAN_POINT('',(-5.46062984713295,1.4228293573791,-4.51758444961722));
#638=CARTESIAN_POINT('',(-5.45397352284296,1.44788148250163,-4.59893369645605));
#639=CARTESIAN_POINT('',(-5.44428778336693,1.48389078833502,-4.7648970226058));
#640=CARTESIAN_POINT('',(-5.44125744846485,1.49485154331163,-4.84951026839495));
#641=CARTESIAN_POINT('',(-5.43924327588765,1.50216234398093,-5.01664165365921));
#642=CARTESIAN_POINT('',(-5.4401308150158,1.49897678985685,-5.09913823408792));
#643=CARTESIAN_POINT('',(-5.44555143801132,1.47916189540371,-5.26237244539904));
#644=CARTESIAN_POINT('',(-5.4500844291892,1.46253289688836,-5.34311012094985));
#645=CARTESIAN_POINT('',(-5.46220889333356,1.41657159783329,-5.4999543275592));
#646=CARTESIAN_POINT('',(-5.46977678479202,1.38733711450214,-5.57609147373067));
#647=CARTESIAN_POINT('',(-5.48711904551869,1.31707074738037,-5.72243773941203));
#648=CARTESIAN_POINT('',(-5.49689375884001,1.27603702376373,-5.79264593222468));
#649=CARTESIAN_POINT('',(-5.51790549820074,1.18192697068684,-5.92735947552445));
#650=CARTESIAN_POINT('',(-5.52917693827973,1.12853345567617,-5.99163790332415));
#651=CARTESIAN_POINT('',(-5.55171924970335,1.0118234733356,-6.11047346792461));
#652=CARTESIAN_POINT('',(-5.56299012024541,0.948504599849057,-6.1650282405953));
#653=CARTESIAN_POINT('',(-5.58454727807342,0.81212026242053,-6.26400514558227));
#654=CARTESIAN_POINT('',(-5.59480760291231,0.738876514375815,-6.30818774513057));
#655=CARTESIAN_POINT('',(-5.61290415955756,0.585731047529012,-6.38354307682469));
#656=CARTESIAN_POINT('',(-5.62074195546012,0.505833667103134,-6.41472420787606));
#657=CARTESIAN_POINT('',(-5.63208923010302,0.355187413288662,-6.45909522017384));
#658=CARTESIAN_POINT('',(-5.63609819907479,0.285091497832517,-6.47439901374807));
#659=CARTESIAN_POINT('',(-5.64148302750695,0.143335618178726,-6.4948517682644));
#660=CARTESIAN_POINT('',(-5.64285914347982,0.0716758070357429,-6.50000171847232));
#661=CARTESIAN_POINT('',(-5.642858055,0.,-6.5));
#662=B_SPLINE_CURVE_WITH_KNOTS('',3,(#584,#585,#586,#587,#588,#589,#590,#591,#592,#593,#594,
#595,#596,#597,#598,#599,#600,#601,#602,#603,#604,#605,#606,#607,#608,#609,#610,#611,#612,#613,
#614,#615,#616,#617,#618,#619,#620,#621,#622,#623,#624,#625,#626,#627,#628,#629,#630,#631,#632,
#633,#634,#635,#636,#637,#638,#639,#640,#641,#642,#643,#644,#645,#646,#647,#648,#649,#650,#651,
#652,#653,#654,#655,#656,#657,#658,#659,#660,#661),.UNSPECIFIED.,.T.,.F.,(4,2,2,2,2,2,2,2,2,2,2,
2,2,2,2,2,2,2,2,2,2,2,2,2,2,2,2,2,2,2,2,2,2,2,2,2,2,2,4),(0.,0.247838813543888,
0.495798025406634,0.743439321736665,0.991096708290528,1.2438859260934,1.49670744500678,
1.75384041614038,2.01092628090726,2.26223840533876,2.51350388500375,2.75781410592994,
3.00214374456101,3.24921454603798,3.49633373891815,3.75146021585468,4.00659662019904,
4.2628281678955,4.51900406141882,4.76782603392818,5.01662246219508,5.26117607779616,
5.505756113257,5.75510447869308,6.00450181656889,6.26088449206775,6.51725641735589,
6.77211602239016,7.0269109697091,7.27340437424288,7.51989151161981,7.76449941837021,
8.00914548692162,8.26094862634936,8.51281290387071,8.77002078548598,9.02706225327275,
9.24188280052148,9.45668241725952),.UNSPECIFIED.);
#663=CARTESIAN_POINT('',(-5.642858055,0.,-6.5));
#664=VERTEX_POINT('',#663);
#665=EDGE_CURVE('E234',#664,#664,#662,.T.);
#666=ORIENTED_EDGE('',*,*,#665,.T.);
#667=EDGE_LOOP('',(#666));
#668=FACE_BOUND('',#667,.T.);
#669=CARTESIAN_POINT('',(0.,0.,-4.));
#670=DIRECTION('',(0.,0.,1.));
#671=DIRECTION('',(1.,0.,0.));
#672=AXIS2_PLACEMENT_3D('',#669,#670,#671);
#673=CIRCLE('',#672,5.642858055);
#674=CARTESIAN_POINT('',(1.5,-5.43983887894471,-4.));
#675=VERTEX_POINT('',#674);
#676=CARTESIAN_POINT('',(-1.5,-5.43983887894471,-4.));
#677=VERTEX_POINT('',#676);
#678=EDGE_CURVE('E145',#675,#677,#673,.F.);
#679=ORIENTED_EDGE('',*,*,#678,.F.);
#680=DIRECTION('',(0.,0.,1.));
#681=VECTOR('',#680,1.);
#682=CARTESIAN_POINT('',(1.5,-5.43983887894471,-10.));
#683=LINE('',#682,#681);
#684=EDGE_CURVE('E179',#675,#31,#683,.T.);
#685=ORIENTED_EDGE('',*,*,#684,.T.);
#686=ORIENTED_EDGE('',*,*,#52,.T.);
#687=DIRECTION('',(0.,0.,1.));
#688=VECTOR('',#687,1.);
#689=CARTESIAN_POINT('',(1.5,5.43983887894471,-10.));
#690=LINE('',#689,#688);
#691=CARTESIAN_POINT('',(1.5,5.43983887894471,-4.));
#692=VERTEX_POINT('',#691);
#693=EDGE_CURVE('E182',#44,#692,#690,.F.);
#694=ORIENTED_EDGE('',*,*,#693,.T.);
#695=CARTESIAN_POINT('',(-1.5,5.43983887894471,-4.));
#696=VERTEX_POINT('',#695);
#697=EDGE_CURVE('E290',#696,#692,#673,.F.);
#698=ORIENTED_EDGE('',*,*,#697,.F.);
#699=DIRECTION('',(0.,0.,1.));
#700=VECTOR('',#699,1.);
#701=CARTESIAN_POINT('',(-1.5,5.43983887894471,-10.));
#702=LINE('',#701,#700);
#703=EDGE_CURVE('E141',#696,#467,#702,.T.);
#704=ORIENTED_EDGE('',*,*,#703,.T.);
#705=ORIENTED_EDGE('',*,*,#478,.T.);
#706=DIRECTION('',(0.,0.,1.));
#707=VECTOR('',#706,1.);
#708=CARTESIAN_POINT('',(-1.5,-5.43983887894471,-10.));
#709=LINE('',#708,#707);
#710=EDGE_CURVE('E178',#475,#677,#709,.F.);
#711=ORIENTED_EDGE('',*,*,#710,.T.);
#712=EDGE_LOOP('',(#679,#685,#686,#694,#698,#704,#705,#711));
#713=FACE_BOUND('',#712,.T.);
#714=ADVANCED_FACE('F224',(#498,#583,#668,#713),#487,.F.);
#715=CARTESIAN_POINT('',(-1.5,23.9829507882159,-13.8298133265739));
#716=CARTESIAN_POINT('',(-1.5,23.1697960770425,-13.0182561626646));
#717=CARTESIAN_POINT('',(-1.5,22.3565720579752,-12.2067684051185));
#718=CARTESIAN_POINT('',(-1.5,20.7298859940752,-10.5840045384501));
#719=CARTESIAN_POINT('',(-1.5,19.9164239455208,-9.77272843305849));
#720=CARTESIAN_POINT('',(-1.5,18.2888908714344,-8.15019003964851));
#721=CARTESIAN_POINT('',(-1.5,17.4748197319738,-7.33892786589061));
#722=CARTESIAN_POINT('',(-1.5,15.8462200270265,-5.71688912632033));
#723=CARTESIAN_POINT('',(-1.5,15.0316914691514,-4.90611255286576));
#724=CARTESIAN_POINT('',(-1.5,13.3679166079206,-3.25150833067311));
#725=CARTESIAN_POINT('',(-1.5,12.5186388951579,-2.40771224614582));
#726=CARTESIAN_POINT('',(-1.5,11.2436084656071,-1.14309787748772));
#727=CARTESIAN_POINT('',(-1.5,10.8184018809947,-0.72172904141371));
#728=CARTESIAN_POINT('',(-1.5,9.9674696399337,0.120480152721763));
#729=CARTESIAN_POINT('',(-1.5,9.54174398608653,0.541320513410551));
#730=CARTESIAN_POINT('',(-1.5,8.68962827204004,1.38212855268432));
#731=CARTESIAN_POINT('',(-1.5,8.26323839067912,1.80209641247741));
#732=CARTESIAN_POINT('',(-1.5,7.40927555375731,2.64084579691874));
#733=CARTESIAN_POINT('',(-1.5,6.98170257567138,3.05962729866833));
#734=CARTESIAN_POINT('',(-1.5,6.3388656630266,3.68624687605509));
#735=CARTESIAN_POINT('',(-1.5,6.12434986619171,3.89485219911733));
#736=CARTESIAN_POINT('',(-1.5,5.69463736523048,4.31136007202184));
#737=CARTESIAN_POINT('',(-1.5,5.47944066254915,4.51926262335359));
#738=CARTESIAN_POINT('',(-1.5,5.0481094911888,4.93407979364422));
#739=CARTESIAN_POINT('',(-1.5,4.83197505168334,5.1409944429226));
#740=CARTESIAN_POINT('',(-1.5,4.39834846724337,5.55339520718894));
#741=CARTESIAN_POINT('',(-1.5,4.1808563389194,5.75888133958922));
#742=CARTESIAN_POINT('',(-1.5,3.90376234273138,6.01802196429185));
#743=CARTESIAN_POINT('',(-1.5,3.84512620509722,6.07270919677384));
#744=CARTESIAN_POINT('',(-1.5,3.72768146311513,6.18189848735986));
#745=CARTESIAN_POINT('',(-1.5,3.66887285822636,6.23640054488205));
#746=CARTESIAN_POINT('',(-1.5,3.49215401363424,6.3995935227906));
#747=CARTESIAN_POINT('',(-1.5,3.37395242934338,6.50796966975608));
#748=CARTESIAN_POINT('',(-1.5,3.13700278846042,6.72317143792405));
#749=CARTESIAN_POINT('',(-1.5,3.01825878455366,6.83000151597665));
#750=CARTESIAN_POINT('',(-1.5,2.77941542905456,7.0421331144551));
#751=CARTESIAN_POINT('',(-1.5,2.65931612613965,7.14743468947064));
#752=CARTESIAN_POINT('',(-1.5,2.45761599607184,7.32107625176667));
#753=CARTESIAN_POINT('',(-1.5,2.37654045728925,7.39002559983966));
#754=CARTESIAN_POINT('',(-1.5,2.21332363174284,7.52664946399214));
#755=CARTESIAN_POINT('',(-1.5,2.13118237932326,7.59432402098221));
#756=CARTESIAN_POINT('',(-1.5,1.96490717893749,7.72847699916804));
#757=CARTESIAN_POINT('',(-1.5,1.88076292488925,7.79494269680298));
#758=CARTESIAN_POINT('',(-1.5,1.71065638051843,7.92549614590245));
#759=CARTESIAN_POINT('',(-1.5,1.62469433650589,7.98958421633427));
#760=CARTESIAN_POINT('',(-1.5,1.4489152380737,8.11541002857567));
#761=CARTESIAN_POINT('',(-1.5,1.35905816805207,8.17709235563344));
#762=CARTESIAN_POINT('',(-1.5,1.17582586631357,8.2953591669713));
#763=CARTESIAN_POINT('',(-1.5,1.08244624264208,8.35193696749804));
#764=CARTESIAN_POINT('',(-1.5,0.892287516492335,8.45646544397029));
#765=CARTESIAN_POINT('',(-1.5,0.79555982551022,8.50450780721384));
#766=CARTESIAN_POINT('',(-1.5,0.596885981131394,8.58809068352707));
#767=CARTESIAN_POINT('',(-1.5,0.494957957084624,8.62367162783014));
#768=CARTESIAN_POINT('',(-1.5,0.341566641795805,8.66233817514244));
#769=CARTESIAN_POINT('',(-1.5,0.291923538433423,8.67265748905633));
#770=CARTESIAN_POINT('',(-1.5,0.191872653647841,8.68858310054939));
#771=CARTESIAN_POINT('',(-1.5,0.141464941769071,8.694189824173));
#772=CARTESIAN_POINT('',(-1.5,0.0404708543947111,8.70029847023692));
#773=CARTESIAN_POINT('',(-1.5,-0.0101146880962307,8.7008139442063));
#774=CARTESIAN_POINT('',(-1.5,-0.111080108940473,8.69673902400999));
#775=CARTESIAN_POINT('',(-1.5,-0.16145996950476,8.69214819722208));
#776=CARTESIAN_POINT('',(-1.5,-0.261112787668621,8.6782367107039));
#777=CARTESIAN_POINT('',(-1.5,-0.310391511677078,8.66895654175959));
#778=CARTESIAN_POINT('',(-1.5,-0.407983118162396,8.64623193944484));
#779=CARTESIAN_POINT('',(-1.5,-0.456295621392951,8.63278590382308));
#780=CARTESIAN_POINT('',(-1.5,-0.552012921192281,8.60229924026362));
#781=CARTESIAN_POINT('',(-1.5,-0.59941226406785,8.58524170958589));
#782=CARTESIAN_POINT('',(-1.5,-0.693027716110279,8.54820030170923));
#783=CARTESIAN_POINT('',(-1.5,-0.739244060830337,8.52821701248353));
#784=CARTESIAN_POINT('',(-1.5,-0.877134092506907,8.46429884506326));
#785=CARTESIAN_POINT('',(-1.5,-0.967112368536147,8.41671652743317));
#786=CARTESIAN_POINT('',(-1.5,-1.14346729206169,8.31523950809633));
#787=CARTESIAN_POINT('',(-1.5,-1.22983935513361,8.26133708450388));
#788=CARTESIAN_POINT('',(-1.5,-1.40011689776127,8.14909277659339));
#789=CARTESIAN_POINT('',(-1.5,-1.48401123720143,8.09073413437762));
#790=CARTESIAN_POINT('',(-1.5,-1.64961606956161,7.97110725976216));
#791=CARTESIAN_POINT('',(-1.5,-1.73132761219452,7.90984046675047));
#792=CARTESIAN_POINT('',(-1.5,-1.89397218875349,7.78454603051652));
#793=CARTESIAN_POINT('',(-1.5,-1.97488799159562,7.72049612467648));
#794=CARTESIAN_POINT('',(-1.5,-2.13544471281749,7.59080709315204));
#795=CARTESIAN_POINT('',(-1.5,-2.21508549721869,7.52516780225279));
#796=CARTESIAN_POINT('',(-1.5,-2.37316238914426,7.3928600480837));
#797=CARTESIAN_POINT('',(-1.5,-2.45160103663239,7.32619461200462));
#798=CARTESIAN_POINT('',(-1.5,-2.60767842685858,7.19194269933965));
#799=CARTESIAN_POINT('',(-1.5,-2.68531720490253,7.12435626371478));
#800=CARTESIAN_POINT('',(-1.5,-2.91396863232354,6.92342200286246));
#801=CARTESIAN_POINT('',(-1.5,-3.06408132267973,6.78905078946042));
#802=CARTESIAN_POINT('',(-1.5,-3.36265984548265,6.51848828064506));
#803=CARTESIAN_POINT('',(-1.5,-3.51112561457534,6.38229691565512));
#804=CARTESIAN_POINT('',(-1.5,-3.80689780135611,6.10862812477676));
#805=CARTESIAN_POINT('',(-1.5,-3.95420408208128,5.97115055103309));
#806=CARTESIAN_POINT('',(-1.5,-4.2479512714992,5.69527329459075));
#807=CARTESIAN_POINT('',(-1.5,-4.39439217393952,5.55687360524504));
#808=CARTESIAN_POINT('',(-1.5,-4.83309667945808,5.14032506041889));
#809=CARTESIAN_POINT('',(-1.5,-5.12438996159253,4.86115489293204));
#810=CARTESIAN_POINT('',(-1.5,-5.70539561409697,4.30121832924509));
#811=CARTESIAN_POINT('',(-1.5,-5.99510809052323,4.02045204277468));
#812=CARTESIAN_POINT('',(-1.5,-6.57050259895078,3.46077976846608));
#813=CARTESIAN_POINT('',(-1.5,-6.85619526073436,3.18188470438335));
#814=CARTESIAN_POINT('',(-1.5,-7.42688642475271,2.62337574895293));
#815=CARTESIAN_POINT('',(-1.5,-7.71188491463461,2.34376184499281));
#816=CARTESIAN_POINT('',(-1.5,-8.56587556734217,1.50442258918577));
#817=CARTESIAN_POINT('',(-1.5,-9.13412608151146,0.94394286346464));
#818=CARTESIAN_POINT('',(-1.5,-10.2940945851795,-0.202420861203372));
#819=CARTESIAN_POINT('',(-1.5,-10.8857636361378,-0.788354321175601));
#820=CARTESIAN_POINT('',(-1.5,-12.0683546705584,-1.96097714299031));
#821=CARTESIAN_POINT('',(-1.5,-12.6592766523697,-2.5476665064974));
#822=CARTESIAN_POINT('',(-1.5,-14.4315473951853,-4.30867310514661));
#823=CARTESIAN_POINT('',(-1.5,-15.6121804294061,-5.48371043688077));
#824=CARTESIAN_POINT('',(-1.5,-17.9916039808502,-7.85372184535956));
#825=CARTESIAN_POINT('',(-1.5,-19.190379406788,-9.04871106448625));
#826=CARTESIAN_POINT('',(-1.5,-20.9880092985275,-10.8414978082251));
#827=CARTESIAN_POINT('',(-1.5,-21.5870724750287,-11.439086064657));
#828=CARTESIAN_POINT('',(-1.5,-22.7850878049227,-12.6343735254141));
#829=CARTESIAN_POINT('',(-1.5,-23.384039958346,-13.2320727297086));
#830=CARTESIAN_POINT('',(-1.5,-23.9829507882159,-13.8298133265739));
#831=B_SPLINE_CURVE_WITH_KNOTS('',3,(#715,#716,#717,#718,#719,#720,#721,#722,#723,#724,#725,
#726,#727,#728,#729,#730,#731,#732,#733,#734,#735,#736,#737,#738,#739,#740,#741,#742,#743,#744,
#745,#746,#747,#748,#749,#750,#751,#752,#753,#754,#755,#756,#757,#758,#759,#760,#761,#762,#763,
#764,#765,#766,#767,#768,#769,#770,#771,#772,#773,#774,#775,#776,#777,#778,#779,#780,#781,#782,
#783,#784,#785,#786,#787,#788,#789,#790,#791,#792,#793,#794,#795,#796,#797,#798,#799,#800,#801,
#802,#803,#804,#805,#806,#807,#808,#809,#810,#811,#812,#813,#814,#815,#816,#817,#818,#819,#820,
#821,#822,#823,#824,#825,#826,#827,#828,#829,#830),.UNSPECIFIED.,.F.,.F.,(4,2,2,2,2,2,2,2,2,2,2,
2,2,2,2,2,2,2,2,2,2,2,2,2,2,2,2,2,2,2,2,2,2,2,2,2,2,2,2,2,2,2,2,2,2,2,2,2,2,2,2,2,2,2,2,2,2,4),
(0.,3.44653605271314,6.89312922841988,10.3409868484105,13.7887887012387,17.3803581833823,
19.1762340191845,20.9721008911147,22.767547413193,24.5630283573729,25.4606903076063,
26.358350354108,27.2559826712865,28.1536040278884,28.3941447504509,28.6346862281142,
29.1157761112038,29.5949495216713,30.0741057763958,30.3933849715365,30.7126539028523,
31.0343095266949,31.3559218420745,31.6827820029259,32.0100641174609,32.3335843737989,
32.6560450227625,32.807966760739,32.959874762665,33.1113783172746,33.2628947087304,
33.4131246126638,33.5634123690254,33.7144197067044,33.8653967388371,34.1703035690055,
34.4755868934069,34.7820808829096,35.0884247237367,35.3979910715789,35.7075897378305,
36.0164043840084,36.3252053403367,36.9295836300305,37.5339850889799,38.1384569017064,
38.742933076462,39.9533293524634,41.1636433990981,42.3613996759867,43.559177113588,
45.9536288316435,48.451729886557,50.949836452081,55.9469807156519,61.0249285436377,
63.5634114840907,66.1018937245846),.UNSPECIFIED.);
#832=EDGE_CURVE('E207',#399,#465,#831,.T.);
#833=ORIENTED_EDGE('',*,*,#832,.F.);
#834=ORIENTED_EDGE('',*,*,#400,.F.);
#835=EDGE_CURVE('E126',#471,#395,#831,.T.);
#836=ORIENTED_EDGE('',*,*,#835,.F.);
#837=ORIENTED_EDGE('',*,*,#472,.F.);
#838=EDGE_LOOP('',(#833,#834,#836,#837));
#839=FACE_BOUND('',#838,.T.);
#840=ADVANCED_FACE('F214',(#839),#61,.T.);
#841=CARTESIAN_POINT('',(-1.5,10.8972473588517,-32.2036033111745));
#842=DIRECTION('',(-1.,0.,0.));
#843=DIRECTION('',(0.,-1.,0.));
#844=AXIS2_PLACEMENT_3D('',#841,#842,#843);
#845=PLANE('',#844);
#846=ORIENTED_EDGE('',*,*,#476,.T.);
#847=ORIENTED_EDGE('',*,*,#835,.T.);
#848=ORIENTED_EDGE('',*,*,#396,.F.);
#849=DIRECTION('',(0.,1.,0.));
#850=VECTOR('',#849,1.);
#851=CARTESIAN_POINT('',(-1.5,10.8972473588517,-4.));
#852=LINE('',#851,#850);
#853=EDGE_CURVE('E128',#387,#677,#852,.T.);
#854=ORIENTED_EDGE('',*,*,#853,.T.);
#855=ORIENTED_EDGE('',*,*,#710,.F.);
#856=EDGE_LOOP('',(#846,#847,#848,#854,#855));
#857=FACE_BOUND('',#856,.T.);
#858=ADVANCED_FACE('F123',(#857),#845,.F.);
#859=CARTESIAN_POINT('',(1.5,10.8972473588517,-32.2036033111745));
#860=DIRECTION('',(1.,0.,0.));
#861=DIRECTION('',(0.,1.,0.));
#862=AXIS2_PLACEMENT_3D('',#859,#860,#861);
#863=PLANE('',#862);
#864=DIRECTION('',(0.,-1.,0.));
#865=VECTOR('',#864,1.);
#866=CARTESIAN_POINT('',(1.5,10.8972473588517,-4.));
#867=LINE('',#866,#865);
#868=EDGE_CURVE('E149',#675,#378,#867,.T.);
#869=ORIENTED_EDGE('',*,*,#868,.T.);
#870=ORIENTED_EDGE('',*,*,#379,.T.);
#871=ORIENTED_EDGE('',*,*,#181,.T.);
#872=ORIENTED_EDGE('',*,*,#32,.T.);
#873=ORIENTED_EDGE('',*,*,#684,.F.);
#874=EDGE_LOOP('',(#869,#870,#871,#872,#873));
#875=FACE_BOUND('',#874,.T.);
#876=ADVANCED_FACE('F218',(#875),#863,.F.);
#877=CARTESIAN_POINT('',(0.,0.,-4.));
#878=DIRECTION('',(0.,0.,1.));
#879=DIRECTION('',(1.,0.,0.));
#880=AXIS2_PLACEMENT_3D('',#877,#878,#879);
#881=PLANE('',#880);
#882=ORIENTED_EDGE('',*,*,#678,.T.);
#883=ORIENTED_EDGE('',*,*,#853,.F.);
#884=ORIENTED_EDGE('',*,*,#388,.F.);
#885=ORIENTED_EDGE('',*,*,#868,.F.);
#886=EDGE_LOOP('',(#882,#883,#884,#885));
#887=FACE_BOUND('',#886,.T.);
#888=ADVANCED_FACE('F140',(#887),#881,.T.);
#889=ORIENTED_EDGE('',*,*,#697,.T.);
#890=EDGE_CURVE('E151',#416,#692,#867,.T.);
#891=ORIENTED_EDGE('',*,*,#890,.F.);
#892=ORIENTED_EDGE('',*,*,#417,.F.);
#893=EDGE_CURVE('E144',#696,#407,#852,.T.);
#894=ORIENTED_EDGE('',*,*,#893,.F.);
#895=EDGE_LOOP('',(#889,#891,#892,#894));
#896=FACE_BOUND('',#895,.T.);
#897=ADVANCED_FACE('F298',(#896),#881,.T.);
#898=ORIENTED_EDGE('',*,*,#45,.T.);
#899=ORIENTED_EDGE('',*,*,#192,.T.);
#900=ORIENTED_EDGE('',*,*,#423,.F.);
#901=ORIENTED_EDGE('',*,*,#890,.T.);
#902=ORIENTED_EDGE('',*,*,#693,.F.);
#903=EDGE_LOOP('',(#898,#899,#900,#901,#902));
#904=FACE_BOUND('',#903,.T.);
#905=ADVANCED_FACE('F223',(#904),#863,.F.);
#906=ORIENTED_EDGE('',*,*,#893,.T.);
#907=ORIENTED_EDGE('',*,*,#408,.T.);
#908=ORIENTED_EDGE('',*,*,#832,.T.);
#909=ORIENTED_EDGE('',*,*,#468,.T.);
#910=ORIENTED_EDGE('',*,*,#703,.F.);
#911=EDGE_LOOP('',(#906,#907,#908,#909,#910));
#912=FACE_BOUND('',#911,.T.);
#913=ADVANCED_FACE('F217',(#912),#845,.F.);
#914=CARTESIAN_POINT('',(-11.,0.,-5.));
#915=DIRECTION('',(1.,0.,0.));
#916=DIRECTION('',(0.,0.,-1.));
#917=AXIS2_PLACEMENT_3D('',#914,#915,#916);
#918=CYLINDRICAL_SURFACE('',#917,1.5);
#919=ORIENTED_EDGE('',*,*,#284,.T.);
#920=EDGE_LOOP('',(#919));
#921=FACE_BOUND('',#920,.T.);
#922=ORIENTED_EDGE('',*,*,#665,.F.);
#923=EDGE_LOOP('',(#922));
#924=FACE_BOUND('',#923,.T.);
#925=ADVANCED_FACE('F247',(#921,#924),#918,.F.);
#926=ORIENTED_EDGE('',*,*,#369,.T.);
#927=EDGE_LOOP('',(#926));
#928=FACE_BOUND('',#927,.T.);
#929=ORIENTED_EDGE('',*,*,#580,.F.);
#930=EDGE_LOOP('',(#929));
#931=FACE_BOUND('',#930,.T.);
#932=ADVANCED_FACE('F244',(#928,#931),#918,.F.);
#933=CARTESIAN_POINT('',(0.,0.,-10.));
#934=DIRECTION('',(0.,0.,-1.));
#935=DIRECTION('',(-1.,0.,0.));
#936=AXIS2_PLACEMENT_3D('',#933,#934,#935);
#937=CONICAL_SURFACE('',#936,6.042858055,0.785398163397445);
#938=ORIENTED_EDGE('',*,*,#495,.F.);
#939=EDGE_LOOP('',(#938));
#940=FACE_BOUND('',#939,.T.);
#941=ORIENTED_EDGE('',*,*,#452,.F.);
#942=EDGE_LOOP('',(#941));
#943=FACE_BOUND('',#942,.T.);
#944=ADVANCED_FACE('F47',(#940,#943),#937,.F.);
#945=CLOSED_SHELL('',(#56,#197,#439,#459,#482,#714,#840,#858,#876,#888,#897,#905,#913,#925,#932,#944));
#946=MANIFOLD_SOLID_BREP('B2',#945);
#947=ADVANCED_BREP_SHAPE_REPRESENTATION('',(#18,#946),#14);
#948=SHAPE_DEFINITION_REPRESENTATION(#9,#947);
ENDSEC;
END-ISO-10303-21;
